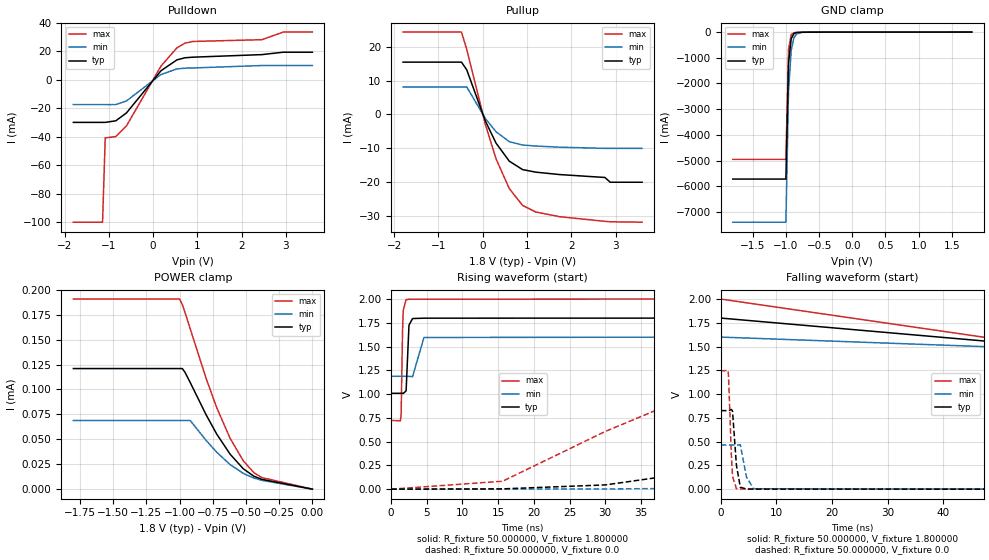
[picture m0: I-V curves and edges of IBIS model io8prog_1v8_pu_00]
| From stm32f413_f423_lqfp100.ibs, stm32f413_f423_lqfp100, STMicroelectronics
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|   Model io8prog_1v8_pu_00
[Model]  io8prog_1v8_pu_00
Model_type I/O
Polarity   Non-Inverting
Enable   Active-Low
Vinl =   0.540000V
Vinh =   1.260000V
Vmeas =  0.900000V
Cref =   100.000000pF
Rref =   1.000000k
Vref =   1.800000V
C_comp   2.595400pF   2.437600pF   2.808600pF
[Temperature Range]   25.000000   0.125000k   -40.000000
[Pullup Reference]   1.800000V   1.600000V   2.000000V
[Pulldown Reference]   0.0V   0.0V   0.0V
[POWER Clamp Reference]   1.800000V   1.600000V   2.000000V
[GND Clamp Reference]   0.0V   0.0V   0.0V
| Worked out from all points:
|   slope of the pulldown table from 0 to 0.27 V, typ, clamps not added: 31 ohm
|   slope of the pullup table from 0 to 0.27 V, typ, clamps not added: 34.9 ohm
|   GND clamp passes 1 mA (typ) near -0.57 V on its own axis
|   rising waveform, R_fixture 50.000000, V_fixture 1.800000: 20-80 % time 213ps typ, 327ps min, 177ps max; typ from 1.01 V to 1.8 V
|   rising waveform, R_fixture 50.000000, V_fixture 0.0: 20-80 % time 42.8ns typ, 83.8ns min, 21ns max; typ from 0.001 V to 0.827 V
|   falling waveform, R_fixture 50.000000, V_fixture 1.800000: 20-80 % time 93.2ns typ, 132ns min, 90.3ns max; typ from 1.8 V to 1.01 V
|   falling waveform, R_fixture 50.000000, V_fixture 0.0: 20-80 % time 642ps typ, 956ps min, 473ps max; typ from 0.827 V to 0.001 V
[Pulldown]
|Voltage   I(typ)   I(min)   I(max)
-1.8V     -30mA      -17.52mA   -100mA
-1.14V    -30mA      -17.52mA   -100mA
-1.08V    -30mA      -17.52mA   -40.9mA
-840mV    -28.88mA   -17.52mA   -39.94mA
-600mV    -23.35mA   -14.94mA   -32.45mA
180mV     6.236mA    3.598mA    9.492mA
540mV     13.85mA    7.499mA    22.29mA
720mV     15.32mA    8.029mA    25.55mA
900mV     15.74mA    8.167mA    26.76mA
2.46V     17.54mA    9.892mA    28.01mA
2.94V     19.22mA    9.892mA    33.34mA
3.6V      19.22mA    9.892mA    33.34mA
[Pullup]
|Voltage   I(typ)   I(min)   I(max)
-1.8V     15.46mA    8.102mA    24.33mA
-480mV    15.46mA    8.102mA    24.33mA
-360mV    13.15mA    8.102mA    19.18mA
60mV      -1.95mA    -1.198mA   -2.977mA
300mV     -8.441mA   -5.092mA   -13.07mA
600mV     -13.78mA   -8.025mA   -21.88mA
900mV     -16.27mA   -9.02mA    -26.86mA
1.2V      -17.03mA   -9.318mA   -28.8mA
1.74V     -17.74mA   -9.658mA   -30.18mA
2.76V     -18.6mA    -10mA      -31.55mA
2.88V     -20mA      -10mA      -31.68mA
3.6V      -20mA      -10mA      -31.8mA
[GND_clamp]
|Voltage   I(typ)   I(min)   I(max)
-1.8V     -5.722A    -7.401A    -4.956A
-1V       -5.722A    -7.401A    -4.956A
-960mV    -1.203A    -2.294A    -680.3mA
-920mV    -260.8mA   -717.4mA   -103.7mA
-880mV    -62.26mA   -228.9mA   -23.84mA
-840mV    -19.05mA   -76.32mA   -11.31mA
-760mV    -5.573mA   -11.66mA   -6.2mA
-640mV    -2.048mA   -2.413mA   -2.197mA
1.8V      0A         0A         0A
[POWER_clamp]
|Voltage   I(typ)   I(min)   I(max)
-1.8V     121uA      68.85uA    190.7uA
-1V       121uA      68.85uA    190.7uA
-980mV    121uA      68.85uA    185.3uA
-960mV    117.4uA    68.85uA    177.7uA
-920mV    107uA      68.85uA    160.9uA
-800mV    74.53uA    48.91uA    111uA
-720mV    55.17uA    36.99uA    81.65uA
-620mV    35.16uA    24.73uA    51.11uA
-520mV    20.42uA    15.79uA    28.41uA
-440mV    12.93uA    11.16uA    16.44uA
-380mV    9.841uA    8.859uA    11.63uA
0V        0A         11.03nA    0A
[Ramp]
| variable   typ   min   max
dV/dt_r  0.49583/42.72068n   0.27818/83.74677n   0.74705/21.01396n
dV/dt_f  0.47466/41.75130n   0.24750/72.88393n   0.76637/23.31048n
R_load = 50.000000
[Rising Waveform]
R_fixture= 50.000000
V_fixture= 1.800000
V_fixture_min= 1.600000
V_fixture_max= 2.000000
|time   V(typ)   V(min)   V(max)
0s        1.009V     1.188V     722.7mV
1.301ns   1.009V     1.188V     720.2mV
1.401ns   1.009V     1.188V     781mV
1.602ns   1.009V     1.188V     1.666V
1.702ns   1.007V     1.188V     1.881V
2.102ns   1.035V     1.188V     1.994V
2.503ns   1.725V     1.187V     1.998V
3.003ns   1.795V     1.184V     1.999V
4.605ns   1.799V     1.596V     1.999V
49.85ns   1.8V       1.6V       2V
[Rising Waveform]
R_fixture= 50.000000
V_fixture= 0.0
V_fixture_min= 0.0
V_fixture_max= 0.0
|time   V(typ)   V(min)   V(max)
0s        740.2uV    788.6uV    721.8uV
15.62ns   3.87mV     1.668mV    84.31mV
30.03ns   45.5mV     3.32mV     608.5mV
43.24ns   185.8mV    9.183mV    1.022V
51.65ns   304.1mV    16.83mV    1.142V
64.86ns   479.8mV    39.57mV    1.21V
96.1ns    726.3mV    146.6mV    1.242V
145.3ns   815.3mV    321.9mV    1.246V
269.1ns   827mV      456.1mV    1.246V
598.2ns   827.2mV    464.4mV    1.246V
[Falling Waveform]
R_fixture= 50.000000
V_fixture= 1.800000
V_fixture_min= 1.600000
V_fixture_max= 2.000000
|time   V(typ)   V(min)   V(max)
0s        1.8V       1.6V       2V
150.2ns   1.035V     1.282V     725mV
300.3ns   1.009V     1.194V     722.7mV
450.5ns   1.009V     1.188V     722.7mV
14.86us   1.009V     1.188V     722.7mV
[Falling Waveform]
R_fixture= 50.000000
V_fixture= 0.0
V_fixture_min= 0.0
V_fixture_max= 0.0
|time   V(typ)   V(min)   V(max)
0s        827.2mV    464.4mV    1.246V
1.301ns   826.5mV    464.4mV    1.248V
1.401ns   826.2mV    464.4mV    1.17V
1.902ns   838.8mV    464.4mV    349.5mV
2.102ns   821.2mV    464.1mV    135.4mV
2.803ns   252.4mV    464.6mV    6.742mV
3.504ns   20.77mV    468mV      2.985mV
4.605ns   2.091mV    128.4mV    2.837mV
5.906ns   1.693mV    5.252mV    2.824mV
49.85ns   740.2uV    788.6uV    721.8uV
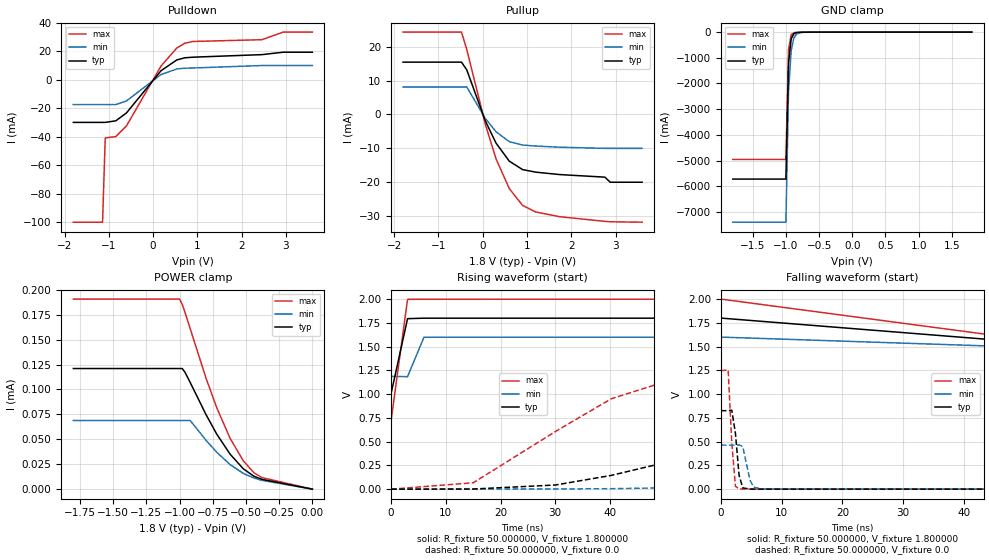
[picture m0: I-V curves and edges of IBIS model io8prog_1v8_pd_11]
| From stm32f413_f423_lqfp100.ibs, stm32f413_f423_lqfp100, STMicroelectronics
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|   Model io8prog_1v8_pd_11
[Model]  io8prog_1v8_pd_11
Model_type I/O
Polarity   Non-Inverting
Enable   Active-Low
Vinl =   0.540000V
Vinh =   1.260000V
Vmeas =  0.900000V
Cref =   100.000000pF
Rref =   1.000000k
Vref =   1.800000V
C_comp   2.595400pF   2.437600pF   2.808600pF
[Temperature Range]   25.000000   0.125000k   -40.000000
[Pullup Reference]   1.800000V   1.600000V   2.000000V
[Pulldown Reference]   0.0V   0.0V   0.0V
[POWER Clamp Reference]   1.800000V   1.600000V   2.000000V
[GND Clamp Reference]   0.0V   0.0V   0.0V
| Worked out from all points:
|   slope of the pulldown table from 0 to 0.27 V, typ, clamps not added: 31 ohm
|   slope of the pullup table from 0 to 0.27 V, typ, clamps not added: 34.9 ohm
|   GND clamp passes 1 mA (typ) near -0.57 V on its own axis
|   rising waveform, R_fixture 50.000000, V_fixture 1.800000: 20-80 % time 1.82ns typ, 1.79ns min, 1.81ns max; typ from 1.01 V to 1.8 V
|   rising waveform, R_fixture 50.000000, V_fixture 0.0: 20-80 % time 42.7ns typ, 82.4ns min, 21ns max; typ from 0 V to 0.826 V
|   falling waveform, R_fixture 50.000000, V_fixture 1.800000: 20-80 % time 93.2ns typ, 131ns min, 90.3ns max; typ from 1.8 V to 1.01 V
|   falling waveform, R_fixture 50.000000, V_fixture 0.0: 20-80 % time 755ps typ, 980ps min, 713ps max; typ from 0.826 V to 0 V
[Pulldown]
|Voltage   I(typ)   I(min)   I(max)
-1.8V     -30mA      -17.52mA   -100mA
-1.14V    -30mA      -17.52mA   -100mA
-1.08V    -30mA      -17.52mA   -40.9mA
-840mV    -28.88mA   -17.52mA   -39.94mA
-600mV    -23.35mA   -14.94mA   -32.45mA
180mV     6.236mA    3.598mA    9.492mA
540mV     13.85mA    7.499mA    22.29mA
720mV     15.32mA    8.029mA    25.55mA
900mV     15.74mA    8.167mA    26.76mA
2.46V     17.54mA    9.893mA    28.01mA
2.94V     19.23mA    9.893mA    33.35mA
3.6V      19.23mA    9.893mA    33.35mA
[Pullup]
|Voltage   I(typ)   I(min)   I(max)
-1.8V     15.46mA    8.1mA      24.33mA
-480mV    15.46mA    8.1mA      24.33mA
-360mV    13.15mA    8.1mA      19.18mA
60mV      -1.95mA    -1.198mA   -2.977mA
300mV     -8.441mA   -5.092mA   -13.07mA
600mV     -13.78mA   -8.025mA   -21.88mA
900mV     -16.27mA   -9.02mA    -26.86mA
1.2V      -17.03mA   -9.318mA   -28.8mA
1.74V     -17.74mA   -9.658mA   -30.18mA
2.76V     -18.5mA    -10mA      -31.55mA
2.88V     -20mA      -10mA      -31.68mA
3.6V      -20mA      -10mA      -31.8mA
[GND_clamp]
|Voltage   I(typ)   I(min)   I(max)
-1.8V     -5.722A    -7.401A    -4.956A
-1V       -5.722A    -7.401A    -4.956A
-960mV    -1.203A    -2.294A    -680.3mA
-920mV    -260.8mA   -717.4mA   -103.7mA
-880mV    -62.28mA   -228.9mA   -23.86mA
-840mV    -19.06mA   -76.33mA   -11.32mA
-760mV    -5.585mA   -11.67mA   -6.214mA
-640mV    -2.06mA    -2.422mA   -2.211mA
1.8V      44.31uA    33.68uA    51.4uA
[POWER_clamp]
|Voltage   I(typ)   I(min)   I(max)
-1.8V     121uA      68.85uA    190.7uA
-1V       121uA      68.85uA    190.7uA
-980mV    121uA      68.85uA    185.3uA
-960mV    117.4uA    68.85uA    177.7uA
-920mV    107uA      68.85uA    160.9uA
-800mV    74.53uA    48.91uA    111uA
-720mV    55.17uA    36.99uA    81.65uA
-620mV    35.16uA    24.73uA    51.11uA
-520mV    20.42uA    15.79uA    28.41uA
-440mV    12.93uA    11.16uA    16.44uA
-380mV    9.841uA    8.859uA    11.63uA
0V        0A         11.03nA    0A
[Ramp]
| variable   typ   min   max
dV/dt_r  0.49533/42.68723n   0.27782/83.69974n   0.74670/20.99069n
dV/dt_f  0.47520/41.75159n   0.24786/72.96807n   0.76679/23.30881n
R_load = 50.000000
[Rising Waveform]
R_fixture= 50.000000
V_fixture= 1.800000
V_fixture_min= 1.600000
V_fixture_max= 2.000000
|time   V(typ)   V(min)   V(max)
0s        1.007V     1.186V     721.4mV
3.003ns   1.793V     1.183V     1.996V
6.006ns   1.798V     1.598V     1.997V
297.3ns   1.799V     1.599V     1.999V
[Rising Waveform]
R_fixture= 50.000000
V_fixture= 0.0
V_fixture_min= 0.0
V_fixture_max= 0.0
|time   V(typ)   V(min)   V(max)
0s        195.6uV    220.2uV    196.3uV
15.02ns   1.982mV    442.3uV    67.53mV
30.03ns   43.95mV    2.116mV    606.9mV
40.24ns   145mV      5.355mV    951.1mV
49.25ns   268.7mV    13.57mV    1.115V
60.66ns   424.6mV    29.45mV    1.196V
86.49ns   673.8mV    107.9mV    1.238V
115.9ns   783mV      226.2mV    1.244V
192.2ns   823.2mV    414.1mV    1.245V
299.1ns   825.7mV    463.3mV    1.245V
[Falling Waveform]
R_fixture= 50.000000
V_fixture= 1.800000
V_fixture_min= 1.600000
V_fixture_max= 2.000000
|time   V(typ)   V(min)   V(max)
0s        1.799V     1.599V     1.999V
150.2ns   1.034V     1.281V     723.8mV
300.3ns   1.008V     1.193V     721.4mV
450.5ns   1.007V     1.187V     721.4mV
14.86us   1.007V     1.186V     721.4mV
[Falling Waveform]
R_fixture= 50.000000
V_fixture= 0.0
V_fixture_min= 0.0
V_fixture_max= 0.0
|time   V(typ)   V(min)   V(max)
0s        825.7mV    463.3mV    1.245V
1.201ns   825.4mV    463.3mV    1.254V
1.802ns   830.9mV    463.3mV    491.1mV
2.402ns   588.1mV    462.6mV    29.97mV
3.003ns   147.2mV    465.9mV    2.589mV
3.604ns   13.64mV    449.9mV    1.051mV
4.805ns   938.3uV    93.4mV     939.8uV
5.405ns   729.1uV    22.13mV    932.7uV
6.607ns   678uV      1.506mV    924.8uV
299.1ns   195.6uV    220.2uV    196.3uV
